VERSION 5.8 ;
BUSBITCHARS "[]" ;
DIVIDERCHAR "/" ;
UNITS
  DATABASE MICRONS 1000 ;
END UNITS
LAYER M1
  TYPE ROUTING ;
  DIRECTION HORIZONTAL ;
  PITCH 0.2 ;
  WIDTH 0.1 ;
  SPACING 0.1 ;
END M1
SITE CoreSite
  CLASS CORE ;
  SIZE 1 BY 1 ;
  SYMMETRY X Y ;
END CoreSite
SITE CornerSite
  CLASS PAD ;
  SIZE 1.5 BY 1.5 ;
  SYMMETRY X Y R90 ;
END CornerSite
MACRO FILL1
  CLASS CORE SPACER ;
  ORIGIN 0 0 ;
  SIZE 1 BY 1 ;
  SITE CoreSite ;
END FILL1
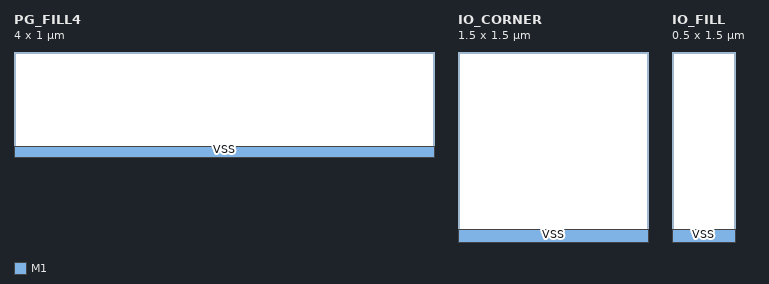
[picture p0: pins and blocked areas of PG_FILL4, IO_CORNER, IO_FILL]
MACRO PG_FILL4
  CLASS CORE ;
  ORIGIN 0 0 ;
  SIZE 4 BY 1 ;
  SITE CoreSite ;
  PIN VSS
    DIRECTION INOUT ;
    USE GROUND ;
    PORT
      LAYER M1 ;
      RECT 0 0 4 0.1 ;
    END
  END VSS
END PG_FILL4
MACRO IO_CORNER
  CLASS ENDCAP BOTTOMLEFT ;
  ORIGIN 0 0 ;
  SIZE 1.5 BY 1.5 ;
  SITE CornerSite ;
  PIN VSS
    DIRECTION INOUT ;
    USE GROUND ;
    PORT
      LAYER M1 ;
      RECT 0 0 1.5 0.1 ;
    END
  END VSS
END IO_CORNER
MACRO IO_FILL
  CLASS PAD SPACER ;
  ORIGIN 0 0 ;
  SIZE 0.5 BY 1.5 ;
  SITE CornerSite ;
  PIN VSS
    DIRECTION INOUT ;
    USE GROUND ;
    PORT
      LAYER M1 ;
      RECT 0 0 0.5 0.1 ;
    END
  END VSS
END IO_FILL
END LIBRARY
